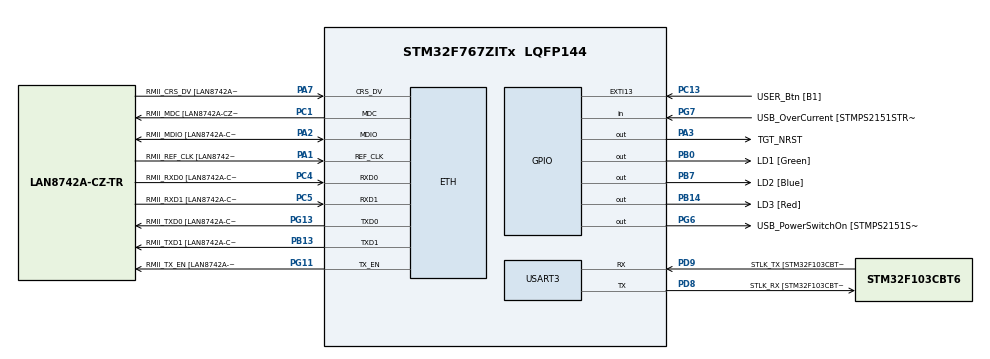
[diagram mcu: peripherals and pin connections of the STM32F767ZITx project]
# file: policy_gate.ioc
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CORTEX_M7.default_mode_Activation=1
ETH.MediaInterface=HAL_ETH_RMII_MODE
ETH.PHY_Name=LAN8742A_PHY_ADDRESS
ETH.PHY_Value=0
ETH.PhyAddress=0
FREERTOS.configTOTAL_HEAP_SIZE=65536
FREERTOS.configUSE_NEWLIB_REENTRANT=1
FREERTOS.configCHECK_FOR_STACK_OVERFLOW=2
FREERTOS.configUSE_MALLOC_FAILED_HOOK=1
Mcu.Family=STM32F7
Mcu.Name=STM32F767ZITx
Mcu.Package=LQFP144
NVIC.PriorityGroup=NVIC_PRIORITYGROUP_4
NVIC.TIM6_DAC_IRQn=true\:15\:0\:false\:false\:true\:false\:false\:true\:true
NVIC.TimeBase=TIM6_DAC_IRQn
NVIC.USART3_IRQn=true\:5\:0\:false\:false\:true\:true\:true\:true\:true
NVIC.TimeBaseIP=TIM6
PA3.GPIO_Label=TGT_NRST
PA3.GPIO_ModeDefaultOutputPP=GPIO_MODE_OUTPUT_OD
PA3.GPIO_PuPd=GPIO_NOPULL
PA3.GPIO_Speed=GPIO_SPEED_FREQ_LOW
PA3.PinState=GPIO_PIN_SET
PA3.Signal=GPIO_Output
PA1.GPIO_Label=RMII_REF_CLK [LAN8742A-CZ-TR_REFCLK0]
PA1.Mode=RMII
PA1.Signal=ETH_REF_CLK
PA10.GPIO_Label=USB_ID
PA10.Signal=USB_OTG_FS_ID
PA11.GPIO_Label=USB_DM
PA11.Signal=USB_OTG_FS_DM
PA12.GPIO_Label=USB_DP
PA12.Signal=USB_OTG_FS_DP
PA13.GPIO_Label=TMS
PA13.Mode=Serial_Wire
PA13.Signal=SYS_JTMS-SWDIO
PA14.GPIO_Label=TCK
PA14.Mode=Serial_Wire
PA14.Signal=SYS_JTCK-SWCLK
PA2.GPIO_Label=RMII_MDIO [LAN8742A-CZ-TR_MDIO]
PA2.Mode=RMII
PA2.Signal=ETH_MDIO
PA7.GPIO_Label=RMII_CRS_DV [LAN8742A-CZ-TR_CRS_DV]
PA7.Mode=RMII
PA7.Signal=ETH_CRS_DV
PA8.GPIO_Label=USB_SOF [TP1]
PA8.Signal=USB_OTG_FS_SOF
PA9.GPIO_Label=USB_VBUS
PA9.Signal=USB_OTG_FS_VBUS
PB0.GPIO_Label=LD1 [Green]
PB0.Signal=GPIO_Output
PB13.GPIO_Label=RMII_TXD1 [LAN8742A-CZ-TR_TXD1]
PB13.Mode=RMII
PB13.Signal=ETH_TXD1
PB14.GPIO_Label=LD3 [Red]
PB14.Signal=GPIO_Output
PB3.GPIO_Label=SWO
PB3.Signal=SYS_JTDO-SWO
PB7.GPIO_Label=LD2 [Blue]
PB7.Signal=GPIO_Output
PC1.GPIO_Label=RMII_MDC [LAN8742A-CZ-TR_MDC]
PC1.Mode=RMII
PC1.Signal=ETH_MDC
PC13.GPIO_Label=USER_Btn [B1]
PC13.Signal=GPXTI13
PC14/OSC32_IN.Mode=LSE-External-Oscillator
PC14/OSC32_IN.Signal=RCC_OSC32_IN
PC15/OSC32_OUT.Mode=LSE-External-Oscillator
PC15/OSC32_OUT.Signal=RCC_OSC32_OUT
PC4.GPIO_Label=RMII_RXD0 [LAN8742A-CZ-TR_RXD0]
PC4.Mode=RMII
PC4.Signal=ETH_RXD0
PC5.GPIO_Label=RMII_RXD1 [LAN8742A-CZ-TR_RXD1]
PC5.Mode=RMII
PC5.Signal=ETH_RXD1
PD8.GPIO_Label=STLK_RX [STM32F103CBT6_PA3]
PD8.Mode=Asynchronous
PD8.Signal=USART3_TX
PD9.GPIO_Label=STLK_TX [STM32F103CBT6_PA2]
PD9.Mode=Asynchronous
PD9.Signal=USART3_RX
PG11.GPIO_Label=RMII_TX_EN [LAN8742A-CZ-TR_TXEN]
PG11.Mode=RMII
PG11.Signal=ETH_TX_EN
PG13.GPIO_Label=RMII_TXD0 [LAN8742A-CZ-TR_TXD0]
PG13.Mode=RMII
PG13.Signal=ETH_TXD0
PG6.GPIO_Label=USB_PowerSwitchOn [STMPS2151STR_EN]
PG6.Signal=GPIO_Output
PG7.GPIO_Label=USB_OverCurrent [STMPS2151STR_FAULT]
PG7.Signal=GPIO_Input
PH0/OSC_IN.GPIO_Label=MCO [STM32F103CBT6_PA8]
PH0/OSC_IN.Mode=HSE-External-Clock-Source
PH0/OSC_IN.Signal=RCC_OSC_IN
PH1/OSC_OUT.Mode=HSE-External-Clock-Source
PH1/OSC_OUT.Signal=RCC_OSC_OUT
ProjectManager.HeapSize=0x200
ProjectManager.StackSize=0x1000
ProjectManager.TargetToolchain=STM32CubeIDE
RCC.48MHZClocksFreq_Value=24000000
RCC.AHBFreq_Value=96000000
RCC.APB1CLKDivider=RCC_HCLK_DIV2
RCC.APB1Freq_Value=48000000
RCC.APB1TimFreq_Value=96000000
RCC.APB2Freq_Value=96000000
RCC.APB2TimFreq_Value=96000000
RCC.CortexFreq_Value=96000000
RCC.HCLKFreq_Value=96000000
RCC.HSE_VALUE=8000000
RCC.HSI_VALUE=16000000
RCC.PLLM=4
RCC.PLLMUL=RCC_PLL_MUL9
RCC.PLLN=96
RCC.PLLQ=4
RCC.PLLSourceVirtual=RCC_PLLSOURCE_HSE
RCC.PRESCALERUSB=RCC_USBCLKSOURCE_PLL_DIV1_5
RCC.SYSCLKFreq_VALUE=96000000
RCC.SYSCLKSource=RCC_SYSCLKSOURCE_PLLCLK
RCC.SYSCLKSourceVirtual=RCC_SYSCLKSOURCE_PLLCLK
RCC.USBFreq_Value=48000000
RCC.VCOOutputFreq_Value=192000000
USART3.VirtualMode-Asynchronous=VM_ASYNC
VP_FREERTOS_VS_CMSIS_V2.Mode=CMSIS_V2
VP_SYS_VS_tim6.Mode=TIM6
board=NUCLEO-F767ZI

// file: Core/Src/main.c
/* USER CODE BEGIN Header */
/**
 ******************************************************************************
 * @file           : main.c
 * @brief          : Main program body
 ******************************************************************************
 * @attention
 *
 * Copyright (c) 2025 STMicroelectronics.
 * All rights reserved.
 *
 * This software is licensed under terms that can be found in the LICENSE file
 * in the root directory of this software component.
 * If no LICENSE file comes with this software, it is provided AS-IS.
 *
 ******************************************************************************
 */
/* USER CODE END Header */
#include "main.h"
#include "string.h"
#include "cmsis_os.h"

/* USER CODE BEGIN Includes */
#include "gateway_platform.h"
#include "gateway_network.h"
#include "paper_experiment.h"
#include <string.h>
/* USER CODE END Includes */

#if defined ( __ICCARM__ ) /*!< IAR Compiler */
#pragma location=0x2007c000
ETH_DMADescTypeDef  DMARxDscrTab[ETH_RX_DESC_CNT]; /* Ethernet Rx DMA Descriptors */
#pragma location=0x2007c0a0
ETH_DMADescTypeDef  DMATxDscrTab[ETH_TX_DESC_CNT]; /* Ethernet Tx DMA Descriptors */

#elif defined ( __CC_ARM )  /* MDK ARM Compiler */

__attribute__((at(0x2007c000))) ETH_DMADescTypeDef  DMARxDscrTab[ETH_RX_DESC_CNT]; /* Ethernet Rx DMA Descriptors */
__attribute__((at(0x2007c0a0))) ETH_DMADescTypeDef  DMATxDscrTab[ETH_TX_DESC_CNT]; /* Ethernet Tx DMA Descriptors */

#elif defined ( __GNUC__ ) /* GNU Compiler */

ETH_DMADescTypeDef DMARxDscrTab[ETH_RX_DESC_CNT] __attribute__((section(".RxDecripSection"))); /* Ethernet Rx DMA Descriptors */
ETH_DMADescTypeDef DMATxDscrTab[ETH_TX_DESC_CNT] __attribute__((section(".TxDecripSection"))); /* Ethernet Tx DMA Descriptors */
#endif

ETH_TxPacketConfig TxConfig __attribute__((section(".gateway_privileged")));

ETH_HandleTypeDef heth __attribute__((section(".gateway_privileged")));

UART_HandleTypeDef huart3 __attribute__((section(".gateway_privileged")));

void SystemClock_Config(void);
static void MPU_Config(void);
static void MX_GPIO_Init(void);
static void MX_ETH_Init(void);
static void MX_USART3_UART_Init(void);

int main(void) {

	/* USER CODE BEGIN 1 */
    extern uint8_t __privileged_data_start__[], __privileged_data_end__[];
    extern uint8_t __privileged_init_start__[], __privileged_init_end__[];
    extern uint8_t __privileged_init_load__[];
    extern uint8_t __gateway_auth_start__[], __gateway_auth_end__[];
    extern uint8_t __gateway_gate_start__[], __gateway_gate_end__[];
    extern uint8_t __gateway_gate_init_start__[], __gateway_gate_init_end__[];
    extern uint8_t __gateway_gate_init_load__[];
    memset(__privileged_data_start__, 0,
           (size_t)(__privileged_data_end__-__privileged_data_start__));
    memcpy(__privileged_init_start__, __privileged_init_load__,
           (size_t)(__privileged_init_end__-__privileged_init_start__));
    memset(__gateway_auth_start__,0,
           (size_t)(__gateway_auth_end__-__gateway_auth_start__));
    memset(__gateway_gate_start__,0,
           (size_t)(__gateway_gate_end__-__gateway_gate_start__));
    memcpy(__gateway_gate_init_start__,__gateway_gate_init_load__,
           (size_t)(__gateway_gate_init_end__-__gateway_gate_init_start__));

	/* USER CODE END 1 */

	/* MPU Configuration--------------------------------------------------------*/
	MPU_Config();

	/* MCU Configuration--------------------------------------------------------*/

	/* Reset of all peripherals, Initializes the Flash interface and the Systick. */
	HAL_Init();

	/* USER CODE BEGIN Init */
    gateway_network_mpu();
#if GATEWAY_R4_CACHES
    SCB_EnableICache();
#endif

	/* USER CODE END Init */

	/* Configure the system clock */
	SystemClock_Config();

	/* Initialize all configured peripherals */
	MX_GPIO_Init();
	MX_ETH_Init();
	MX_USART3_UART_Init();
	/* USER CODE BEGIN 2 */
    gateway_boot_report();
/* USER CODE END 2 */

	/* Init scheduler */
	osKernelInitialize();

	/* Create the thread(s) */

	/* USER CODE BEGIN RTOS_THREADS */
    gateway_platform_start();
/* USER CODE END RTOS_THREADS */

	/* Start scheduler */
	osKernelStart();

	/* We should never get here as control is now taken by the scheduler */

	/* Infinite loop */
	while (1) {

		/* USER CODE BEGIN 3 */
    gateway_panic(GATEWAY_FAULT_STARTUP);
    }
/* USER CODE END 3 */
}

void SystemClock_Config(void) {
	RCC_OscInitTypeDef RCC_OscInitStruct = { 0 };
	RCC_ClkInitTypeDef RCC_ClkInitStruct = { 0 };

	/** Configure LSE Drive Capability
	 */
	HAL_PWR_EnableBkUpAccess();

	/** Configure the main internal regulator output voltage
	 */
	__HAL_RCC_PWR_CLK_ENABLE();
	__HAL_PWR_VOLTAGESCALING_CONFIG(
#if GATEWAY_R4_FAST_CLOCK
        PWR_REGULATOR_VOLTAGE_SCALE1
#else
        PWR_REGULATOR_VOLTAGE_SCALE3
#endif
    );

	/** Initializes the RCC Oscillators according to the specified parameters
	 * in the RCC_OscInitTypeDef structure.
	 */
	RCC_OscInitStruct.OscillatorType = RCC_OSCILLATORTYPE_HSE;
	RCC_OscInitStruct.HSEState = RCC_HSE_BYPASS;
	RCC_OscInitStruct.PLL.PLLState = RCC_PLL_ON;
	RCC_OscInitStruct.PLL.PLLSource = RCC_PLLSOURCE_HSE;
	RCC_OscInitStruct.PLL.PLLM = 4;
	RCC_OscInitStruct.PLL.PLLN =
#if GATEWAY_R4_FAST_CLOCK
        216;
#else
        96;
#endif
	RCC_OscInitStruct.PLL.PLLP = RCC_PLLP_DIV2;
	RCC_OscInitStruct.PLL.PLLQ =
#if GATEWAY_R4_FAST_CLOCK
        9;
#else
        4;
#endif
	RCC_OscInitStruct.PLL.PLLR = 2;
	if (HAL_RCC_OscConfig(&RCC_OscInitStruct) != HAL_OK) {
		Error_Handler();
	}

	/** Activate the Over-Drive mode
	 */
	if (HAL_PWREx_EnableOverDrive() != HAL_OK) {
		Error_Handler();
	}

	/** Initializes the CPU, AHB and APB buses clocks
	 */
	RCC_ClkInitStruct.ClockType = RCC_CLOCKTYPE_HCLK | RCC_CLOCKTYPE_SYSCLK
			| RCC_CLOCKTYPE_PCLK1 | RCC_CLOCKTYPE_PCLK2;
	RCC_ClkInitStruct.SYSCLKSource = RCC_SYSCLKSOURCE_PLLCLK;
	RCC_ClkInitStruct.AHBCLKDivider = RCC_SYSCLK_DIV1;
	RCC_ClkInitStruct.APB1CLKDivider =
#if GATEWAY_R4_FAST_CLOCK
        RCC_HCLK_DIV4;
#else
        RCC_HCLK_DIV2;
#endif
	RCC_ClkInitStruct.APB2CLKDivider =
#if GATEWAY_R4_FAST_CLOCK
        RCC_HCLK_DIV2;
#else
        RCC_HCLK_DIV1;
#endif

	if (HAL_RCC_ClockConfig(&RCC_ClkInitStruct,
#if GATEWAY_R4_FAST_CLOCK
        FLASH_LATENCY_7
#else
        FLASH_LATENCY_3
#endif
        ) != HAL_OK) {
		Error_Handler();
	}
}

static void MX_ETH_Init(void) {

	static uint8_t MACAddr[6];

	heth.Instance = ETH;
	MACAddr[0] = 0x00;
	MACAddr[1] = 0x80;
	MACAddr[2] = 0xE1;
	MACAddr[3] = 0x00;
	MACAddr[4] = 0x00;
	MACAddr[5] = 0x00;
	heth.Init.MACAddr = &MACAddr[0];
	heth.Init.MediaInterface = HAL_ETH_RMII_MODE;
	heth.Init.TxDesc = DMATxDscrTab;
	heth.Init.RxDesc = DMARxDscrTab;
	heth.Init.RxBuffLen = 1524;

	/* USER CODE BEGIN MACADDRESS */
    MACAddr[0]=0x02; MACAddr[1]=0x80; MACAddr[2]=0xE1;
    uint32_t uid=HAL_GetUIDw0() ^ HAL_GetUIDw1() ^ HAL_GetUIDw2();
    MACAddr[3]=(uint8_t)(uid>>16); MACAddr[4]=(uint8_t)(uid>>8); MACAddr[5]=(uint8_t)uid;

	/* USER CODE END MACADDRESS */

	if (HAL_ETH_Init(&heth) != HAL_OK) {
		Error_Handler();
	}

	memset(&TxConfig, 0, sizeof(ETH_TxPacketConfig));
	TxConfig.Attributes = ETH_TX_PACKETS_FEATURES_CSUM
			| ETH_TX_PACKETS_FEATURES_CRCPAD;
	TxConfig.ChecksumCtrl = ETH_CHECKSUM_IPHDR_PAYLOAD_INSERT_PHDR_CALC;
	TxConfig.CRCPadCtrl = ETH_CRC_PAD_INSERT;

}

static void MX_USART3_UART_Init(void) {

	huart3.Instance = USART3;
	huart3.Init.BaudRate =
#if GATEWAY_PAPER_TIMING
        921600;
#else
        115200;
#endif
	huart3.Init.WordLength = UART_WORDLENGTH_8B;
	huart3.Init.StopBits = UART_STOPBITS_1;
	huart3.Init.Parity = UART_PARITY_NONE;
	huart3.Init.Mode = UART_MODE_TX_RX;
	huart3.Init.HwFlowCtl = UART_HWCONTROL_NONE;
	huart3.Init.OverSampling = UART_OVERSAMPLING_16;
	huart3.Init.OneBitSampling = UART_ONE_BIT_SAMPLE_DISABLE;
	huart3.AdvancedInit.AdvFeatureInit = UART_ADVFEATURE_NO_INIT;
	if (HAL_UART_Init(&huart3) != HAL_OK) {
		Error_Handler();
	}

}

static void MX_GPIO_Init(void) {
	GPIO_InitTypeDef GPIO_InitStruct = { 0 };

	/* GPIO Ports Clock Enable */
	__HAL_RCC_GPIOC_CLK_ENABLE();
	__HAL_RCC_GPIOH_CLK_ENABLE();
	__HAL_RCC_GPIOA_CLK_ENABLE();
	__HAL_RCC_GPIOB_CLK_ENABLE();
	__HAL_RCC_GPIOD_CLK_ENABLE();
	__HAL_RCC_GPIOG_CLK_ENABLE();

	/*Configure GPIO pin Output Level */
	HAL_GPIO_WritePin(GPIOB, LD1_Pin | LD3_Pin | LD2_Pin, GPIO_PIN_RESET);

	/*Configure GPIO pin Output Level */
	HAL_GPIO_WritePin(USB_PowerSwitchOn_GPIO_Port, USB_PowerSwitchOn_Pin,
			GPIO_PIN_RESET);

	/*Configure GPIO pin Output Level */
	HAL_GPIO_WritePin(TGT_NRST_GPIO_Port, TGT_NRST_Pin, GPIO_PIN_SET);

	/*Configure GPIO pin : USER_Btn_Pin */
	GPIO_InitStruct.Pin = USER_Btn_Pin;
	GPIO_InitStruct.Mode = GPIO_MODE_IT_RISING;
	GPIO_InitStruct.Pull = GPIO_NOPULL;
	HAL_GPIO_Init(USER_Btn_GPIO_Port, &GPIO_InitStruct);

	/*Configure GPIO pins : LD1_Pin LD3_Pin LD2_Pin */
	GPIO_InitStruct.Pin = LD1_Pin | LD3_Pin | LD2_Pin;
	GPIO_InitStruct.Mode = GPIO_MODE_OUTPUT_PP;
	GPIO_InitStruct.Pull = GPIO_NOPULL;
	GPIO_InitStruct.Speed = GPIO_SPEED_FREQ_LOW;
	HAL_GPIO_Init(GPIOB, &GPIO_InitStruct);

	/*Configure GPIO pin : USB_PowerSwitchOn_Pin */
	GPIO_InitStruct.Pin = USB_PowerSwitchOn_Pin;
	GPIO_InitStruct.Mode = GPIO_MODE_OUTPUT_PP;
	GPIO_InitStruct.Pull = GPIO_NOPULL;
	GPIO_InitStruct.Speed = GPIO_SPEED_FREQ_LOW;
	HAL_GPIO_Init(USB_PowerSwitchOn_GPIO_Port, &GPIO_InitStruct);

	/*Configure GPIO pin : USB_OverCurrent_Pin */
	GPIO_InitStruct.Pin = USB_OverCurrent_Pin;
	GPIO_InitStruct.Mode = GPIO_MODE_INPUT;
	GPIO_InitStruct.Pull = GPIO_NOPULL;
	HAL_GPIO_Init(USB_OverCurrent_GPIO_Port, &GPIO_InitStruct);

	/*Configure GPIO pins : USB_SOF_Pin USB_ID_Pin USB_DM_Pin USB_DP_Pin */
	GPIO_InitStruct.Pin = USB_SOF_Pin | USB_ID_Pin | USB_DM_Pin | USB_DP_Pin;
	GPIO_InitStruct.Mode = GPIO_MODE_AF_PP;
	GPIO_InitStruct.Pull = GPIO_NOPULL;
	GPIO_InitStruct.Speed = GPIO_SPEED_FREQ_VERY_HIGH;
	GPIO_InitStruct.Alternate = GPIO_AF10_OTG_FS;
	HAL_GPIO_Init(GPIOA, &GPIO_InitStruct);

	/*Configure GPIO pin : TGT_NRST_Pin */
	GPIO_InitStruct.Pin = TGT_NRST_Pin;
	GPIO_InitStruct.Mode = GPIO_MODE_OUTPUT_OD;
	GPIO_InitStruct.Pull = GPIO_NOPULL;
	GPIO_InitStruct.Speed = GPIO_SPEED_FREQ_LOW;
	HAL_GPIO_Init(TGT_NRST_GPIO_Port, &GPIO_InitStruct);

	/*Configure GPIO pin : USB_VBUS_Pin */
	GPIO_InitStruct.Pin = USB_VBUS_Pin;
	GPIO_InitStruct.Mode = GPIO_MODE_INPUT;
	GPIO_InitStruct.Pull = GPIO_NOPULL;
	HAL_GPIO_Init(USB_VBUS_GPIO_Port, &GPIO_InitStruct);

}

/* MPU Configuration */

void MPU_Config(void) {
	MPU_Region_InitTypeDef MPU_InitStruct = { 0 };

	/* Disables the MPU */
	HAL_MPU_Disable();

	/** Initializes and configures the Region and the memory to be protected
	 */
	MPU_InitStruct.Enable = MPU_REGION_ENABLE;
	MPU_InitStruct.Number = MPU_REGION_NUMBER0;
	MPU_InitStruct.BaseAddress = 0x0;
	MPU_InitStruct.Size = MPU_REGION_SIZE_4GB;
	MPU_InitStruct.SubRegionDisable = 0x87;
	MPU_InitStruct.TypeExtField = MPU_TEX_LEVEL0;
	MPU_InitStruct.AccessPermission = MPU_REGION_NO_ACCESS;
	MPU_InitStruct.DisableExec = MPU_INSTRUCTION_ACCESS_DISABLE;
	MPU_InitStruct.IsShareable = MPU_ACCESS_SHAREABLE;
	MPU_InitStruct.IsCacheable = MPU_ACCESS_NOT_CACHEABLE;
	MPU_InitStruct.IsBufferable = MPU_ACCESS_NOT_BUFFERABLE;

	HAL_MPU_ConfigRegion(&MPU_InitStruct);
	/* Enables the MPU */
	HAL_MPU_Enable(MPU_PRIVILEGED_DEFAULT);

}

void HAL_TIM_PeriodElapsedCallback(TIM_HandleTypeDef *htim) {
	if (htim->Instance == TIM6) {
		HAL_IncTick();
	}
}

void Error_Handler(void) {
	/* USER CODE BEGIN Error_Handler_Debug */
    gateway_panic(GATEWAY_FAULT_STARTUP);
/* USER CODE END Error_Handler_Debug */
}
